# Generated by FakeRAM 2.0 (routing-friendly)
VERSION 5.7 ;
BUSBITCHARS "[]" ;
PROPERTYDEFINITIONS
  MACRO width INTEGER ;
  MACRO depth INTEGER ;
  MACRO banks INTEGER ;
END PROPERTYDEFINITIONS
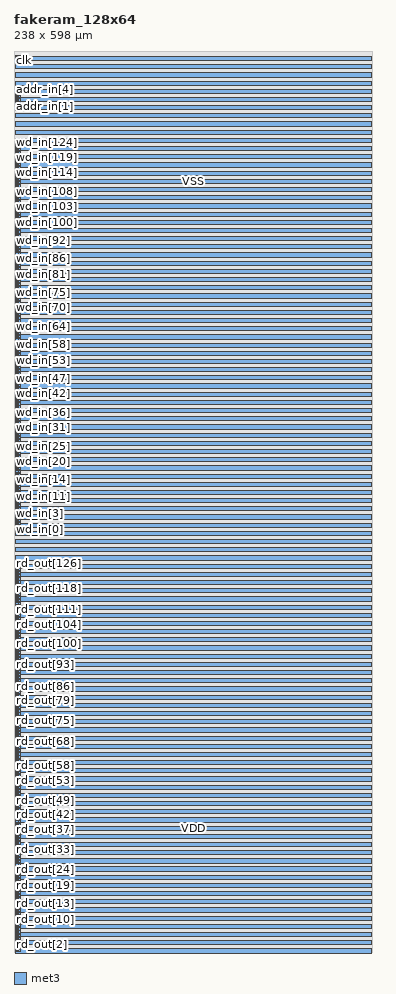
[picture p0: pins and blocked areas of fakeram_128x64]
MACRO fakeram_128x64
  PROPERTY width 128 ;
  PROPERTY depth 64 ;
  PROPERTY banks 1 ;
  FOREIGN fakeram_128x64 0 0 ;
  SYMMETRY X Y R90 ;
  SIZE 238.000 BY 598.000 ;
  CLASS BLOCK ;
  PIN rd_out[0]
    DIRECTION OUTPUT ;
    USE SIGNAL ;
    PORT
      LAYER met3 ;
      RECT 1.000 0.680 3.000 1.380 ;
    END
    PORT
      LAYER met3 ;
      RECT 1.000 0.330 4.000 1.730 ;
    END
  END rd_out[0]
  PIN rd_out[1]
    DIRECTION OUTPUT ;
    USE SIGNAL ;
    PORT
      LAYER met3 ;
      RECT 1.000 2.720 3.000 3.420 ;
    END
    PORT
      LAYER met3 ;
      RECT 1.000 2.370 4.000 3.770 ;
    END
  END rd_out[1]
  PIN rd_out[2]
    DIRECTION OUTPUT ;
    USE SIGNAL ;
    PORT
      LAYER met3 ;
      RECT 1.000 4.760 3.000 5.460 ;
    END
    PORT
      LAYER met3 ;
      RECT 1.000 4.410 4.000 5.810 ;
    END
  END rd_out[2]
  PIN rd_out[3]
    DIRECTION OUTPUT ;
    USE SIGNAL ;
    PORT
      LAYER met3 ;
      RECT 1.000 6.800 3.000 7.500 ;
    END
    PORT
      LAYER met3 ;
      RECT 1.000 6.450 4.000 7.850 ;
    END
  END rd_out[3]
  PIN rd_out[4]
    DIRECTION OUTPUT ;
    USE SIGNAL ;
    PORT
      LAYER met3 ;
      RECT 1.000 8.840 3.000 9.540 ;
    END
    PORT
      LAYER met3 ;
      RECT 1.000 8.490 4.000 9.890 ;
    END
  END rd_out[4]
  PIN rd_out[5]
    DIRECTION OUTPUT ;
    USE SIGNAL ;
    PORT
      LAYER met3 ;
      RECT 1.000 10.880 3.000 11.580 ;
    END
    PORT
      LAYER met3 ;
      RECT 1.000 10.530 4.000 11.930 ;
    END
  END rd_out[5]
  PIN rd_out[6]
    DIRECTION OUTPUT ;
    USE SIGNAL ;
    PORT
      LAYER met3 ;
      RECT 1.000 12.920 3.000 13.620 ;
    END
    PORT
      LAYER met3 ;
      RECT 1.000 12.570 4.000 13.970 ;
    END
  END rd_out[6]
  PIN rd_out[7]
    DIRECTION OUTPUT ;
    USE SIGNAL ;
    PORT
      LAYER met3 ;
      RECT 1.000 14.960 3.000 15.660 ;
    END
    PORT
      LAYER met3 ;
      RECT 1.000 14.610 4.000 16.010 ;
    END
  END rd_out[7]
  PIN rd_out[8]
    DIRECTION OUTPUT ;
    USE SIGNAL ;
    PORT
      LAYER met3 ;
      RECT 1.000 17.000 3.000 17.700 ;
    END
    PORT
      LAYER met3 ;
      RECT 1.000 16.650 4.000 18.050 ;
    END
  END rd_out[8]
  PIN rd_out[9]
    DIRECTION OUTPUT ;
    USE SIGNAL ;
    PORT
      LAYER met3 ;
      RECT 1.000 19.040 3.000 19.740 ;
    END
    PORT
      LAYER met3 ;
      RECT 1.000 18.690 4.000 20.090 ;
    END
  END rd_out[9]
  PIN rd_out[10]
    DIRECTION OUTPUT ;
    USE SIGNAL ;
    PORT
      LAYER met3 ;
      RECT 1.000 21.080 3.000 21.780 ;
    END
    PORT
      LAYER met3 ;
      RECT 1.000 20.730 4.000 22.130 ;
    END
  END rd_out[10]
  PIN rd_out[11]
    DIRECTION OUTPUT ;
    USE SIGNAL ;
    PORT
      LAYER met3 ;
      RECT 1.000 23.120 3.000 23.820 ;
    END
    PORT
      LAYER met3 ;
      RECT 1.000 22.770 4.000 24.170 ;
    END
  END rd_out[11]
  PIN rd_out[12]
    DIRECTION OUTPUT ;
    USE SIGNAL ;
    PORT
      LAYER met3 ;
      RECT 1.000 25.160 3.000 25.860 ;
    END
    PORT
      LAYER met3 ;
      RECT 1.000 24.810 4.000 26.210 ;
    END
  END rd_out[12]
  PIN rd_out[13]
    DIRECTION OUTPUT ;
    USE SIGNAL ;
    PORT
      LAYER met3 ;
      RECT 1.000 27.200 3.000 27.900 ;
    END
    PORT
      LAYER met3 ;
      RECT 1.000 26.850 4.000 28.250 ;
    END
  END rd_out[13]
  PIN rd_out[14]
    DIRECTION OUTPUT ;
    USE SIGNAL ;
    PORT
      LAYER met3 ;
      RECT 1.000 29.240 3.000 29.940 ;
    END
    PORT
      LAYER met3 ;
      RECT 1.000 28.890 4.000 30.290 ;
    END
  END rd_out[14]
  PIN rd_out[15]
    DIRECTION OUTPUT ;
    USE SIGNAL ;
    PORT
      LAYER met3 ;
      RECT 1.000 31.280 3.000 31.980 ;
    END
    PORT
      LAYER met3 ;
      RECT 1.000 30.930 4.000 32.330 ;
    END
  END rd_out[15]
  PIN rd_out[16]
    DIRECTION OUTPUT ;
    USE SIGNAL ;
    PORT
      LAYER met3 ;
      RECT 1.000 33.320 3.000 34.020 ;
    END
    PORT
      LAYER met3 ;
      RECT 1.000 32.970 4.000 34.370 ;
    END
  END rd_out[16]
  PIN rd_out[17]
    DIRECTION OUTPUT ;
    USE SIGNAL ;
    PORT
      LAYER met3 ;
      RECT 1.000 35.360 3.000 36.060 ;
    END
    PORT
      LAYER met3 ;
      RECT 1.000 35.010 4.000 36.410 ;
    END
  END rd_out[17]
  PIN rd_out[18]
    DIRECTION OUTPUT ;
    USE SIGNAL ;
    PORT
      LAYER met3 ;
      RECT 1.000 37.400 3.000 38.100 ;
    END
    PORT
      LAYER met3 ;
      RECT 1.000 37.050 4.000 38.450 ;
    END
  END rd_out[18]
  PIN rd_out[19]
    DIRECTION OUTPUT ;
    USE SIGNAL ;
    PORT
      LAYER met3 ;
      RECT 1.000 39.440 3.000 40.140 ;
    END
    PORT
      LAYER met3 ;
      RECT 1.000 39.090 4.000 40.490 ;
    END
  END rd_out[19]
  PIN rd_out[20]
    DIRECTION OUTPUT ;
    USE SIGNAL ;
    PORT
      LAYER met3 ;
      RECT 1.000 41.480 3.000 42.180 ;
    END
    PORT
      LAYER met3 ;
      RECT 1.000 41.130 4.000 42.530 ;
    END
  END rd_out[20]
  PIN rd_out[21]
    DIRECTION OUTPUT ;
    USE SIGNAL ;
    PORT
      LAYER met3 ;
      RECT 1.000 43.520 3.000 44.220 ;
    END
    PORT
      LAYER met3 ;
      RECT 1.000 43.170 4.000 44.570 ;
    END
  END rd_out[21]
  PIN rd_out[22]
    DIRECTION OUTPUT ;
    USE SIGNAL ;
    PORT
      LAYER met3 ;
      RECT 1.000 45.560 3.000 46.260 ;
    END
    PORT
      LAYER met3 ;
      RECT 1.000 45.210 4.000 46.610 ;
    END
  END rd_out[22]
  PIN rd_out[23]
    DIRECTION OUTPUT ;
    USE SIGNAL ;
    PORT
      LAYER met3 ;
      RECT 1.000 47.600 3.000 48.300 ;
    END
    PORT
      LAYER met3 ;
      RECT 1.000 47.250 4.000 48.650 ;
    END
  END rd_out[23]
  PIN rd_out[24]
    DIRECTION OUTPUT ;
    USE SIGNAL ;
    PORT
      LAYER met3 ;
      RECT 1.000 49.640 3.000 50.340 ;
    END
    PORT
      LAYER met3 ;
      RECT 1.000 49.290 4.000 50.690 ;
    END
  END rd_out[24]
  PIN rd_out[25]
    DIRECTION OUTPUT ;
    USE SIGNAL ;
    PORT
      LAYER met3 ;
      RECT 1.000 51.680 3.000 52.380 ;
    END
    PORT
      LAYER met3 ;
      RECT 1.000 51.330 4.000 52.730 ;
    END
  END rd_out[25]
  PIN rd_out[26]
    DIRECTION OUTPUT ;
    USE SIGNAL ;
    PORT
      LAYER met3 ;
      RECT 1.000 53.720 3.000 54.420 ;
    END
    PORT
      LAYER met3 ;
      RECT 1.000 53.370 4.000 54.770 ;
    END
  END rd_out[26]
  PIN rd_out[27]
    DIRECTION OUTPUT ;
    USE SIGNAL ;
    PORT
      LAYER met3 ;
      RECT 1.000 55.760 3.000 56.460 ;
    END
    PORT
      LAYER met3 ;
      RECT 1.000 55.410 4.000 56.810 ;
    END
  END rd_out[27]
  PIN rd_out[28]
    DIRECTION OUTPUT ;
    USE SIGNAL ;
    PORT
      LAYER met3 ;
      RECT 1.000 57.800 3.000 58.500 ;
    END
    PORT
      LAYER met3 ;
      RECT 1.000 57.450 4.000 58.850 ;
    END
  END rd_out[28]
  PIN rd_out[29]
    DIRECTION OUTPUT ;
    USE SIGNAL ;
    PORT
      LAYER met3 ;
      RECT 1.000 59.840 3.000 60.540 ;
    END
    PORT
      LAYER met3 ;
      RECT 1.000 59.490 4.000 60.890 ;
    END
  END rd_out[29]
  PIN rd_out[30]
    DIRECTION OUTPUT ;
    USE SIGNAL ;
    PORT
      LAYER met3 ;
      RECT 1.000 61.880 3.000 62.580 ;
    END
    PORT
      LAYER met3 ;
      RECT 1.000 61.530 4.000 62.930 ;
    END
  END rd_out[30]
  PIN rd_out[31]
    DIRECTION OUTPUT ;
    USE SIGNAL ;
    PORT
      LAYER met3 ;
      RECT 1.000 63.920 3.000 64.620 ;
    END
    PORT
      LAYER met3 ;
      RECT 1.000 63.570 4.000 64.970 ;
    END
  END rd_out[31]
  PIN rd_out[32]
    DIRECTION OUTPUT ;
    USE SIGNAL ;
    PORT
      LAYER met3 ;
      RECT 1.000 65.960 3.000 66.660 ;
    END
    PORT
      LAYER met3 ;
      RECT 1.000 65.610 4.000 67.010 ;
    END
  END rd_out[32]
  PIN rd_out[33]
    DIRECTION OUTPUT ;
    USE SIGNAL ;
    PORT
      LAYER met3 ;
      RECT 1.000 68.000 3.000 68.700 ;
    END
    PORT
      LAYER met3 ;
      RECT 1.000 67.650 4.000 69.050 ;
    END
  END rd_out[33]
  PIN rd_out[34]
    DIRECTION OUTPUT ;
    USE SIGNAL ;
    PORT
      LAYER met3 ;
      RECT 1.000 70.040 3.000 70.740 ;
    END
    PORT
      LAYER met3 ;
      RECT 1.000 69.690 4.000 71.090 ;
    END
  END rd_out[34]
  PIN rd_out[35]
    DIRECTION OUTPUT ;
    USE SIGNAL ;
    PORT
      LAYER met3 ;
      RECT 1.000 72.080 3.000 72.780 ;
    END
    PORT
      LAYER met3 ;
      RECT 1.000 71.730 4.000 73.130 ;
    END
  END rd_out[35]
  PIN rd_out[36]
    DIRECTION OUTPUT ;
    USE SIGNAL ;
    PORT
      LAYER met3 ;
      RECT 1.000 74.120 3.000 74.820 ;
    END
    PORT
      LAYER met3 ;
      RECT 1.000 73.770 4.000 75.170 ;
    END
  END rd_out[36]
  PIN rd_out[37]
    DIRECTION OUTPUT ;
    USE SIGNAL ;
    PORT
      LAYER met3 ;
      RECT 1.000 76.160 3.000 76.860 ;
    END
    PORT
      LAYER met3 ;
      RECT 1.000 75.810 4.000 77.210 ;
    END
  END rd_out[37]
  PIN rd_out[38]
    DIRECTION OUTPUT ;
    USE SIGNAL ;
    PORT
      LAYER met3 ;
      RECT 1.000 78.200 3.000 78.900 ;
    END
    PORT
      LAYER met3 ;
      RECT 1.000 77.850 4.000 79.250 ;
    END
  END rd_out[38]
  PIN rd_out[39]
    DIRECTION OUTPUT ;
    USE SIGNAL ;
    PORT
      LAYER met3 ;
      RECT 1.000 80.240 3.000 80.940 ;
    END
    PORT
      LAYER met3 ;
      RECT 1.000 79.890 4.000 81.290 ;
    END
  END rd_out[39]
  PIN rd_out[40]
    DIRECTION OUTPUT ;
    USE SIGNAL ;
    PORT
      LAYER met3 ;
      RECT 1.000 82.280 3.000 82.980 ;
    END
    PORT
      LAYER met3 ;
      RECT 1.000 81.930 4.000 83.330 ;
    END
  END rd_out[40]
  PIN rd_out[41]
    DIRECTION OUTPUT ;
    USE SIGNAL ;
    PORT
      LAYER met3 ;
      RECT 1.000 84.320 3.000 85.020 ;
    END
    PORT
      LAYER met3 ;
      RECT 1.000 83.970 4.000 85.370 ;
    END
  END rd_out[41]
  PIN rd_out[42]
    DIRECTION OUTPUT ;
    USE SIGNAL ;
    PORT
      LAYER met3 ;
      RECT 1.000 86.360 3.000 87.060 ;
    END
    PORT
      LAYER met3 ;
      RECT 1.000 86.010 4.000 87.410 ;
    END
  END rd_out[42]
  PIN rd_out[43]
    DIRECTION OUTPUT ;
    USE SIGNAL ;
    PORT
      LAYER met3 ;
      RECT 1.000 88.400 3.000 89.100 ;
    END
    PORT
      LAYER met3 ;
      RECT 1.000 88.050 4.000 89.450 ;
    END
  END rd_out[43]
  PIN rd_out[44]
    DIRECTION OUTPUT ;
    USE SIGNAL ;
    PORT
      LAYER met3 ;
      RECT 1.000 90.440 3.000 91.140 ;
    END
    PORT
      LAYER met3 ;
      RECT 1.000 90.090 4.000 91.490 ;
    END
  END rd_out[44]
  PIN rd_out[45]
    DIRECTION OUTPUT ;
    USE SIGNAL ;
    PORT
      LAYER met3 ;
      RECT 1.000 92.480 3.000 93.180 ;
    END
    PORT
      LAYER met3 ;
      RECT 1.000 92.130 4.000 93.530 ;
    END
  END rd_out[45]
  PIN rd_out[46]
    DIRECTION OUTPUT ;
    USE SIGNAL ;
    PORT
      LAYER met3 ;
      RECT 1.000 94.520 3.000 95.220 ;
    END
    PORT
      LAYER met3 ;
      RECT 1.000 94.170 4.000 95.570 ;
    END
  END rd_out[46]
  PIN rd_out[47]
    DIRECTION OUTPUT ;
    USE SIGNAL ;
    PORT
      LAYER met3 ;
      RECT 1.000 96.560 3.000 97.260 ;
    END
    PORT
      LAYER met3 ;
      RECT 1.000 96.210 4.000 97.610 ;
    END
  END rd_out[47]
  PIN rd_out[48]
    DIRECTION OUTPUT ;
    USE SIGNAL ;
    PORT
      LAYER met3 ;
      RECT 1.000 98.600 3.000 99.300 ;
    END
    PORT
      LAYER met3 ;
      RECT 1.000 98.250 4.000 99.650 ;
    END
  END rd_out[48]
  PIN rd_out[49]
    DIRECTION OUTPUT ;
    USE SIGNAL ;
    PORT
      LAYER met3 ;
      RECT 1.000 100.640 3.000 101.340 ;
    END
    PORT
      LAYER met3 ;
      RECT 1.000 100.290 4.000 101.690 ;
    END
  END rd_out[49]
  PIN rd_out[50]
    DIRECTION OUTPUT ;
    USE SIGNAL ;
    PORT
      LAYER met3 ;
      RECT 1.000 102.680 3.000 103.380 ;
    END
    PORT
      LAYER met3 ;
      RECT 1.000 102.330 4.000 103.730 ;
    END
  END rd_out[50]
  PIN rd_out[51]
    DIRECTION OUTPUT ;
    USE SIGNAL ;
    PORT
      LAYER met3 ;
      RECT 1.000 104.720 3.000 105.420 ;
    END
    PORT
      LAYER met3 ;
      RECT 1.000 104.370 4.000 105.770 ;
    END
  END rd_out[51]
  PIN rd_out[52]
    DIRECTION OUTPUT ;
    USE SIGNAL ;
    PORT
      LAYER met3 ;
      RECT 1.000 106.760 3.000 107.460 ;
    END
    PORT
      LAYER met3 ;
      RECT 1.000 106.410 4.000 107.810 ;
    END
  END rd_out[52]
  PIN rd_out[53]
    DIRECTION OUTPUT ;
    USE SIGNAL ;
    PORT
      LAYER met3 ;
      RECT 1.000 108.800 3.000 109.500 ;
    END
    PORT
      LAYER met3 ;
      RECT 1.000 108.450 4.000 109.850 ;
    END
  END rd_out[53]
  PIN rd_out[54]
    DIRECTION OUTPUT ;
    USE SIGNAL ;
    PORT
      LAYER met3 ;
      RECT 1.000 110.840 3.000 111.540 ;
    END
    PORT
      LAYER met3 ;
      RECT 1.000 110.490 4.000 111.890 ;
    END
  END rd_out[54]
  PIN rd_out[55]
    DIRECTION OUTPUT ;
    USE SIGNAL ;
    PORT
      LAYER met3 ;
      RECT 1.000 112.880 3.000 113.580 ;
    END
    PORT
      LAYER met3 ;
      RECT 1.000 112.530 4.000 113.930 ;
    END
  END rd_out[55]
  PIN rd_out[56]
    DIRECTION OUTPUT ;
    USE SIGNAL ;
    PORT
      LAYER met3 ;
      RECT 1.000 114.920 3.000 115.620 ;
    END
    PORT
      LAYER met3 ;
      RECT 1.000 114.570 4.000 115.970 ;
    END
  END rd_out[56]
  PIN rd_out[57]
    DIRECTION OUTPUT ;
    USE SIGNAL ;
    PORT
      LAYER met3 ;
      RECT 1.000 116.960 3.000 117.660 ;
    END
    PORT
      LAYER met3 ;
      RECT 1.000 116.610 4.000 118.010 ;
    END
  END rd_out[57]
  PIN rd_out[58]
    DIRECTION OUTPUT ;
    USE SIGNAL ;
    PORT
      LAYER met3 ;
      RECT 1.000 119.000 3.000 119.700 ;
    END
    PORT
      LAYER met3 ;
      RECT 1.000 118.650 4.000 120.050 ;
    END
  END rd_out[58]
  PIN rd_out[59]
    DIRECTION OUTPUT ;
    USE SIGNAL ;
    PORT
      LAYER met3 ;
      RECT 1.000 121.040 3.000 121.740 ;
    END
    PORT
      LAYER met3 ;
      RECT 1.000 120.690 4.000 122.090 ;
    END
  END rd_out[59]
  PIN rd_out[60]
    DIRECTION OUTPUT ;
    USE SIGNAL ;
    PORT
      LAYER met3 ;
      RECT 1.000 123.080 3.000 123.780 ;
    END
    PORT
      LAYER met3 ;
      RECT 1.000 122.730 4.000 124.130 ;
    END
  END rd_out[60]
  PIN rd_out[61]
    DIRECTION OUTPUT ;
    USE SIGNAL ;
    PORT
      LAYER met3 ;
      RECT 1.000 125.120 3.000 125.820 ;
    END
    PORT
      LAYER met3 ;
      RECT 1.000 124.770 4.000 126.170 ;
    END
  END rd_out[61]
  PIN rd_out[62]
    DIRECTION OUTPUT ;
    USE SIGNAL ;
    PORT
      LAYER met3 ;
      RECT 1.000 127.160 3.000 127.860 ;
    END
    PORT
      LAYER met3 ;
      RECT 1.000 126.810 4.000 128.210 ;
    END
  END rd_out[62]
  PIN rd_out[63]
    DIRECTION OUTPUT ;
    USE SIGNAL ;
    PORT
      LAYER met3 ;
      RECT 1.000 129.200 3.000 129.900 ;
    END
    PORT
      LAYER met3 ;
      RECT 1.000 128.850 4.000 130.250 ;
    END
  END rd_out[63]
  PIN rd_out[64]
    DIRECTION OUTPUT ;
    USE SIGNAL ;
    PORT
      LAYER met3 ;
      RECT 1.000 131.240 3.000 131.940 ;
    END
    PORT
      LAYER met3 ;
      RECT 1.000 130.890 4.000 132.290 ;
    END
  END rd_out[64]
  PIN rd_out[65]
    DIRECTION OUTPUT ;
    USE SIGNAL ;
    PORT
      LAYER met3 ;
      RECT 1.000 133.280 3.000 133.980 ;
    END
    PORT
      LAYER met3 ;
      RECT 1.000 132.930 4.000 134.330 ;
    END
  END rd_out[65]
  PIN rd_out[66]
    DIRECTION OUTPUT ;
    USE SIGNAL ;
    PORT
      LAYER met3 ;
      RECT 1.000 135.320 3.000 136.020 ;
    END
    PORT
      LAYER met3 ;
      RECT 1.000 134.970 4.000 136.370 ;
    END
  END rd_out[66]
  PIN rd_out[67]
    DIRECTION OUTPUT ;
    USE SIGNAL ;
    PORT
      LAYER met3 ;
      RECT 1.000 137.360 3.000 138.060 ;
    END
    PORT
      LAYER met3 ;
      RECT 1.000 137.010 4.000 138.410 ;
    END
  END rd_out[67]
  PIN rd_out[68]
    DIRECTION OUTPUT ;
    USE SIGNAL ;
    PORT
      LAYER met3 ;
      RECT 1.000 139.400 3.000 140.100 ;
    END
    PORT
      LAYER met3 ;
      RECT 1.000 139.050 4.000 140.450 ;
    END
  END rd_out[68]
  PIN rd_out[69]
    DIRECTION OUTPUT ;
    USE SIGNAL ;
    PORT
      LAYER met3 ;
      RECT 1.000 141.440 3.000 142.140 ;
    END
    PORT
      LAYER met3 ;
      RECT 1.000 141.090 4.000 142.490 ;
    END
  END rd_out[69]
  PIN rd_out[70]
    DIRECTION OUTPUT ;
    USE SIGNAL ;
    PORT
      LAYER met3 ;
      RECT 1.000 143.480 3.000 144.180 ;
    END
    PORT
      LAYER met3 ;
      RECT 1.000 143.130 4.000 144.530 ;
    END
  END rd_out[70]
  PIN rd_out[71]
    DIRECTION OUTPUT ;
    USE SIGNAL ;
    PORT
      LAYER met3 ;
      RECT 1.000 145.520 3.000 146.220 ;
    END
    PORT
      LAYER met3 ;
      RECT 1.000 145.170 4.000 146.570 ;
    END
  END rd_out[71]
  PIN rd_out[72]
    DIRECTION OUTPUT ;
    USE SIGNAL ;
    PORT
      LAYER met3 ;
      RECT 1.000 147.560 3.000 148.260 ;
    END
    PORT
      LAYER met3 ;
      RECT 1.000 147.210 4.000 148.610 ;
    END
  END rd_out[72]
  PIN rd_out[73]
    DIRECTION OUTPUT ;
    USE SIGNAL ;
    PORT
      LAYER met3 ;
      RECT 1.000 149.600 3.000 150.300 ;
    END
    PORT
      LAYER met3 ;
      RECT 1.000 149.250 4.000 150.650 ;
    END
  END rd_out[73]
  PIN rd_out[74]
    DIRECTION OUTPUT ;
    USE SIGNAL ;
    PORT
      LAYER met3 ;
      RECT 1.000 151.640 3.000 152.340 ;
    END
    PORT
      LAYER met3 ;
      RECT 1.000 151.290 4.000 152.690 ;
    END
  END rd_out[74]
  PIN rd_out[75]
    DIRECTION OUTPUT ;
    USE SIGNAL ;
    PORT
      LAYER met3 ;
      RECT 1.000 153.680 3.000 154.380 ;
    END
    PORT
      LAYER met3 ;
      RECT 1.000 153.330 4.000 154.730 ;
    END
  END rd_out[75]
  PIN rd_out[76]
    DIRECTION OUTPUT ;
    USE SIGNAL ;
    PORT
      LAYER met3 ;
      RECT 1.000 155.720 3.000 156.420 ;
    END
    PORT
      LAYER met3 ;
      RECT 1.000 155.370 4.000 156.770 ;
    END
  END rd_out[76]
  PIN rd_out[77]
    DIRECTION OUTPUT ;
    USE SIGNAL ;
    PORT
      LAYER met3 ;
      RECT 1.000 157.760 3.000 158.460 ;
    END
    PORT
      LAYER met3 ;
      RECT 1.000 157.410 4.000 158.810 ;
    END
  END rd_out[77]
  PIN rd_out[78]
    DIRECTION OUTPUT ;
    USE SIGNAL ;
    PORT
      LAYER met3 ;
      RECT 1.000 159.800 3.000 160.500 ;
    END
    PORT
      LAYER met3 ;
      RECT 1.000 159.450 4.000 160.850 ;
    END
  END rd_out[78]
  PIN rd_out[79]
    DIRECTION OUTPUT ;
    USE SIGNAL ;
    PORT
      LAYER met3 ;
      RECT 1.000 161.840 3.000 162.540 ;
    END
    PORT
      LAYER met3 ;
      RECT 1.000 161.490 4.000 162.890 ;
    END
  END rd_out[79]
  PIN rd_out[80]
    DIRECTION OUTPUT ;
    USE SIGNAL ;
    PORT
      LAYER met3 ;
      RECT 1.000 163.880 3.000 164.580 ;
    END
    PORT
      LAYER met3 ;
      RECT 1.000 163.530 4.000 164.930 ;
    END
  END rd_out[80]
  PIN rd_out[81]
    DIRECTION OUTPUT ;
    USE SIGNAL ;
    PORT
      LAYER met3 ;
      RECT 1.000 165.920 3.000 166.620 ;
    END
    PORT
      LAYER met3 ;
      RECT 1.000 165.570 4.000 166.970 ;
    END
  END rd_out[81]
  PIN rd_out[82]
    DIRECTION OUTPUT ;
    USE SIGNAL ;
    PORT
      LAYER met3 ;
      RECT 1.000 167.960 3.000 168.660 ;
    END
    PORT
      LAYER met3 ;
      RECT 1.000 167.610 4.000 169.010 ;
    END
  END rd_out[82]
  PIN rd_out[83]
    DIRECTION OUTPUT ;
    USE SIGNAL ;
    PORT
      LAYER met3 ;
      RECT 1.000 170.000 3.000 170.700 ;
    END
    PORT
      LAYER met3 ;
      RECT 1.000 169.650 4.000 171.050 ;
    END
  END rd_out[83]
  PIN rd_out[84]
    DIRECTION OUTPUT ;
    USE SIGNAL ;
    PORT
      LAYER met3 ;
      RECT 1.000 172.040 3.000 172.740 ;
    END
    PORT
      LAYER met3 ;
      RECT 1.000 171.690 4.000 173.090 ;
    END
  END rd_out[84]
  PIN rd_out[85]
    DIRECTION OUTPUT ;
    USE SIGNAL ;
    PORT
      LAYER met3 ;
      RECT 1.000 174.080 3.000 174.780 ;
    END
    PORT
      LAYER met3 ;
      RECT 1.000 173.730 4.000 175.130 ;
    END
  END rd_out[85]
  PIN rd_out[86]
    DIRECTION OUTPUT ;
    USE SIGNAL ;
    PORT
      LAYER met3 ;
      RECT 1.000 176.120 3.000 176.820 ;
    END
    PORT
      LAYER met3 ;
      RECT 1.000 175.770 4.000 177.170 ;
    END
  END rd_out[86]
  PIN rd_out[87]
    DIRECTION OUTPUT ;
    USE SIGNAL ;
    PORT
      LAYER met3 ;
      RECT 1.000 178.160 3.000 178.860 ;
    END
    PORT
      LAYER met3 ;
      RECT 1.000 177.810 4.000 179.210 ;
    END
  END rd_out[87]
  PIN rd_out[88]
    DIRECTION OUTPUT ;
    USE SIGNAL ;
    PORT
      LAYER met3 ;
      RECT 1.000 180.200 3.000 180.900 ;
    END
    PORT
      LAYER met3 ;
      RECT 1.000 179.850 4.000 181.250 ;
    END
  END rd_out[88]
  PIN rd_out[89]
    DIRECTION OUTPUT ;
    USE SIGNAL ;
    PORT
      LAYER met3 ;
      RECT 1.000 182.240 3.000 182.940 ;
    END
    PORT
      LAYER met3 ;
      RECT 1.000 181.890 4.000 183.290 ;
    END
  END rd_out[89]
  PIN rd_out[90]
    DIRECTION OUTPUT ;
    USE SIGNAL ;
    PORT
      LAYER met3 ;
      RECT 1.000 184.280 3.000 184.980 ;
    END
    PORT
      LAYER met3 ;
      RECT 1.000 183.930 4.000 185.330 ;
    END
  END rd_out[90]
  PIN rd_out[91]
    DIRECTION OUTPUT ;
    USE SIGNAL ;
    PORT
      LAYER met3 ;
      RECT 1.000 186.320 3.000 187.020 ;
    END
    PORT
      LAYER met3 ;
      RECT 1.000 185.970 4.000 187.370 ;
    END
  END rd_out[91]
  PIN rd_out[92]
    DIRECTION OUTPUT ;
    USE SIGNAL ;
    PORT
      LAYER met3 ;
      RECT 1.000 188.360 3.000 189.060 ;
    END
    PORT
      LAYER met3 ;
      RECT 1.000 188.010 4.000 189.410 ;
    END
  END rd_out[92]
  PIN rd_out[93]
    DIRECTION OUTPUT ;
    USE SIGNAL ;
    PORT
      LAYER met3 ;
      RECT 1.000 190.400 3.000 191.100 ;
    END
    PORT
      LAYER met3 ;
      RECT 1.000 190.050 4.000 191.450 ;
    END
  END rd_out[93]
  PIN rd_out[94]
    DIRECTION OUTPUT ;
    USE SIGNAL ;
    PORT
      LAYER met3 ;
      RECT 1.000 192.440 3.000 193.140 ;
    END
    PORT
      LAYER met3 ;
      RECT 1.000 192.090 4.000 193.490 ;
    END
  END rd_out[94]
  PIN rd_out[95]
    DIRECTION OUTPUT ;
    USE SIGNAL ;
    PORT
      LAYER met3 ;
      RECT 1.000 194.480 3.000 195.180 ;
    END
    PORT
      LAYER met3 ;
      RECT 1.000 194.130 4.000 195.530 ;
    END
  END rd_out[95]
  PIN rd_out[96]
    DIRECTION OUTPUT ;
    USE SIGNAL ;
    PORT
      LAYER met3 ;
      RECT 1.000 196.520 3.000 197.220 ;
    END
    PORT
      LAYER met3 ;
      RECT 1.000 196.170 4.000 197.570 ;
    END
  END rd_out[96]
  PIN rd_out[97]
    DIRECTION OUTPUT ;
    USE SIGNAL ;
    PORT
      LAYER met3 ;
      RECT 1.000 198.560 3.000 199.260 ;
    END
    PORT
      LAYER met3 ;
      RECT 1.000 198.210 4.000 199.610 ;
    END
  END rd_out[97]
  PIN rd_out[98]
    DIRECTION OUTPUT ;
    USE SIGNAL ;
    PORT
      LAYER met3 ;
      RECT 1.000 200.600 3.000 201.300 ;
    END
    PORT
      LAYER met3 ;
      RECT 1.000 200.250 4.000 201.650 ;
    END
  END rd_out[98]
  PIN rd_out[99]
    DIRECTION OUTPUT ;
    USE SIGNAL ;
    PORT
      LAYER met3 ;
      RECT 1.000 202.640 3.000 203.340 ;
    END
    PORT
      LAYER met3 ;
      RECT 1.000 202.290 4.000 203.690 ;
    END
  END rd_out[99]
  PIN rd_out[100]
    DIRECTION OUTPUT ;
    USE SIGNAL ;
    PORT
      LAYER met3 ;
      RECT 1.000 204.680 3.000 205.380 ;
    END
    PORT
      LAYER met3 ;
      RECT 1.000 204.330 4.000 205.730 ;
    END
  END rd_out[100]
  PIN rd_out[101]
    DIRECTION OUTPUT ;
    USE SIGNAL ;
    PORT
      LAYER met3 ;
      RECT 1.000 206.720 3.000 207.420 ;
    END
    PORT
      LAYER met3 ;
      RECT 1.000 206.370 4.000 207.770 ;
    END
  END rd_out[101]
  PIN rd_out[102]
    DIRECTION OUTPUT ;
    USE SIGNAL ;
    PORT
      LAYER met3 ;
      RECT 1.000 208.760 3.000 209.460 ;
    END
    PORT
      LAYER met3 ;
      RECT 1.000 208.410 4.000 209.810 ;
    END
  END rd_out[102]
  PIN rd_out[103]
    DIRECTION OUTPUT ;
    USE SIGNAL ;
    PORT
      LAYER met3 ;
      RECT 1.000 210.800 3.000 211.500 ;
    END
    PORT
      LAYER met3 ;
      RECT 1.000 210.450 4.000 211.850 ;
    END
  END rd_out[103]
  PIN rd_out[104]
    DIRECTION OUTPUT ;
    USE SIGNAL ;
    PORT
      LAYER met3 ;
      RECT 1.000 212.840 3.000 213.540 ;
    END
    PORT
      LAYER met3 ;
      RECT 1.000 212.490 4.000 213.890 ;
    END
  END rd_out[104]
  PIN rd_out[105]
    DIRECTION OUTPUT ;
    USE SIGNAL ;
    PORT
      LAYER met3 ;
      RECT 1.000 214.880 3.000 215.580 ;
    END
    PORT
      LAYER met3 ;
      RECT 1.000 214.530 4.000 215.930 ;
    END
  END rd_out[105]
  PIN rd_out[106]
    DIRECTION OUTPUT ;
    USE SIGNAL ;
    PORT
      LAYER met3 ;
      RECT 1.000 216.920 3.000 217.620 ;
    END
    PORT
      LAYER met3 ;
      RECT 1.000 216.570 4.000 217.970 ;
    END
  END rd_out[106]
  PIN rd_out[107]
    DIRECTION OUTPUT ;
    USE SIGNAL ;
    PORT
      LAYER met3 ;
      RECT 1.000 218.960 3.000 219.660 ;
    END
    PORT
      LAYER met3 ;
      RECT 1.000 218.610 4.000 220.010 ;
    END
  END rd_out[107]
  PIN rd_out[108]
    DIRECTION OUTPUT ;
    USE SIGNAL ;
    PORT
      LAYER met3 ;
      RECT 1.000 221.000 3.000 221.700 ;
    END
    PORT
      LAYER met3 ;
      RECT 1.000 220.650 4.000 222.050 ;
    END
  END rd_out[108]
  PIN rd_out[109]
    DIRECTION OUTPUT ;
    USE SIGNAL ;
    PORT
      LAYER met3 ;
      RECT 1.000 223.040 3.000 223.740 ;
    END
    PORT
      LAYER met3 ;
      RECT 1.000 222.690 4.000 224.090 ;
    END
  END rd_out[109]
  PIN rd_out[110]
    DIRECTION OUTPUT ;
    USE SIGNAL ;
    PORT
      LAYER met3 ;
      RECT 1.000 225.080 3.000 225.780 ;
    END
    PORT
      LAYER met3 ;
      RECT 1.000 224.730 4.000 226.130 ;
    END
  END rd_out[110]
  PIN rd_out[111]
    DIRECTION OUTPUT ;
    USE SIGNAL ;
    PORT
      LAYER met3 ;
      RECT 1.000 227.120 3.000 227.820 ;
    END
    PORT
      LAYER met3 ;
      RECT 1.000 226.770 4.000 228.170 ;
    END
  END rd_out[111]
  PIN rd_out[112]
    DIRECTION OUTPUT ;
    USE SIGNAL ;
    PORT
      LAYER met3 ;
      RECT 1.000 229.160 3.000 229.860 ;
    END
    PORT
      LAYER met3 ;
      RECT 1.000 228.810 4.000 230.210 ;
    END
  END rd_out[112]
  PIN rd_out[113]
    DIRECTION OUTPUT ;
    USE SIGNAL ;
    PORT
      LAYER met3 ;
      RECT 1.000 231.200 3.000 231.900 ;
    END
    PORT
      LAYER met3 ;
      RECT 1.000 230.850 4.000 232.250 ;
    END
  END rd_out[113]
  PIN rd_out[114]
    DIRECTION OUTPUT ;
    USE SIGNAL ;
    PORT
      LAYER met3 ;
      RECT 1.000 233.240 3.000 233.940 ;
    END
    PORT
      LAYER met3 ;
      RECT 1.000 232.890 4.000 234.290 ;
    END
  END rd_out[114]
  PIN rd_out[115]
    DIRECTION OUTPUT ;
    USE SIGNAL ;
    PORT
      LAYER met3 ;
      RECT 1.000 235.280 3.000 235.980 ;
    END
    PORT
      LAYER met3 ;
      RECT 1.000 234.930 4.000 236.330 ;
    END
  END rd_out[115]
  PIN rd_out[116]
    DIRECTION OUTPUT ;
    USE SIGNAL ;
    PORT
      LAYER met3 ;
      RECT 1.000 237.320 3.000 238.020 ;
    END
    PORT
      LAYER met3 ;
      RECT 1.000 236.970 4.000 238.370 ;
    END
  END rd_out[116]
  PIN rd_out[117]
    DIRECTION OUTPUT ;
    USE SIGNAL ;
    PORT
      LAYER met3 ;
      RECT 1.000 239.360 3.000 240.060 ;
    END
    PORT
      LAYER met3 ;
      RECT 1.000 239.010 4.000 240.410 ;
    END
  END rd_out[117]
  PIN rd_out[118]
    DIRECTION OUTPUT ;
    USE SIGNAL ;
    PORT
      LAYER met3 ;
      RECT 1.000 241.400 3.000 242.100 ;
    END
    PORT
      LAYER met3 ;
      RECT 1.000 241.050 4.000 242.450 ;
    END
  END rd_out[118]
  PIN rd_out[119]
    DIRECTION OUTPUT ;
    USE SIGNAL ;
    PORT
      LAYER met3 ;
      RECT 1.000 243.440 3.000 244.140 ;
    END
    PORT
      LAYER met3 ;
      RECT 1.000 243.090 4.000 244.490 ;
    END
  END rd_out[119]
  PIN rd_out[120]
    DIRECTION OUTPUT ;
    USE SIGNAL ;
    PORT
      LAYER met3 ;
      RECT 1.000 245.480 3.000 246.180 ;
    END
    PORT
      LAYER met3 ;
      RECT 1.000 245.130 4.000 246.530 ;
    END
  END rd_out[120]
  PIN rd_out[121]
    DIRECTION OUTPUT ;
    USE SIGNAL ;
    PORT
      LAYER met3 ;
      RECT 1.000 247.520 3.000 248.220 ;
    END
    PORT
      LAYER met3 ;
      RECT 1.000 247.170 4.000 248.570 ;
    END
  END rd_out[121]
  PIN rd_out[122]
    DIRECTION OUTPUT ;
    USE SIGNAL ;
    PORT
      LAYER met3 ;
      RECT 1.000 249.560 3.000 250.260 ;
    END
    PORT
      LAYER met3 ;
      RECT 1.000 249.210 4.000 250.610 ;
    END
  END rd_out[122]
  PIN rd_out[123]
    DIRECTION OUTPUT ;
    USE SIGNAL ;
    PORT
      LAYER met3 ;
      RECT 1.000 251.600 3.000 252.300 ;
    END
    PORT
      LAYER met3 ;
      RECT 1.000 251.250 4.000 252.650 ;
    END
  END rd_out[123]
  PIN rd_out[124]
    DIRECTION OUTPUT ;
    USE SIGNAL ;
    PORT
      LAYER met3 ;
      RECT 1.000 253.640 3.000 254.340 ;
    END
    PORT
      LAYER met3 ;
      RECT 1.000 253.290 4.000 254.690 ;
    END
  END rd_out[124]
  PIN rd_out[125]
    DIRECTION OUTPUT ;
    USE SIGNAL ;
    PORT
      LAYER met3 ;
      RECT 1.000 255.680 3.000 256.380 ;
    END
    PORT
      LAYER met3 ;
      RECT 1.000 255.330 4.000 256.730 ;
    END
  END rd_out[125]
  PIN rd_out[126]
    DIRECTION OUTPUT ;
    USE SIGNAL ;
    PORT
      LAYER met3 ;
      RECT 1.000 257.720 3.000 258.420 ;
    END
    PORT
      LAYER met3 ;
      RECT 1.000 257.370 4.000 258.770 ;
    END
  END rd_out[126]
  PIN rd_out[127]
    DIRECTION OUTPUT ;
    USE SIGNAL ;
    PORT
      LAYER met3 ;
      RECT 1.000 259.760 3.000 260.460 ;
    END
    PORT
      LAYER met3 ;
      RECT 1.000 259.410 4.000 260.810 ;
    END
  END rd_out[127]
  PIN wd_in[0]
    DIRECTION INPUT ;
    USE SIGNAL ;
    PORT
      LAYER met3 ;
      RECT 1.000 280.160 3.000 280.860 ;
    END
    PORT
      LAYER met3 ;
      RECT 1.000 279.810 4.000 281.210 ;
    END
  END wd_in[0]
  PIN wd_in[1]
    DIRECTION INPUT ;
    USE SIGNAL ;
    PORT
      LAYER met3 ;
      RECT 1.000 282.200 3.000 282.900 ;
    END
    PORT
      LAYER met3 ;
      RECT 1.000 281.850 4.000 283.250 ;
    END
  END wd_in[1]
  PIN wd_in[2]
    DIRECTION INPUT ;
    USE SIGNAL ;
    PORT
      LAYER met3 ;
      RECT 1.000 284.240 3.000 284.940 ;
    END
    PORT
      LAYER met3 ;
      RECT 1.000 283.890 4.000 285.290 ;
    END
  END wd_in[2]
  PIN wd_in[3]
    DIRECTION INPUT ;
    USE SIGNAL ;
    PORT
      LAYER met3 ;
      RECT 1.000 286.280 3.000 286.980 ;
    END
    PORT
      LAYER met3 ;
      RECT 1.000 285.930 4.000 287.330 ;
    END
  END wd_in[3]
  PIN wd_in[4]
    DIRECTION INPUT ;
    USE SIGNAL ;
    PORT
      LAYER met3 ;
      RECT 1.000 288.320 3.000 289.020 ;
    END
    PORT
      LAYER met3 ;
      RECT 1.000 287.970 4.000 289.370 ;
    END
  END wd_in[4]
  PIN wd_in[5]
    DIRECTION INPUT ;
    USE SIGNAL ;
    PORT
      LAYER met3 ;
      RECT 1.000 290.360 3.000 291.060 ;
    END
    PORT
      LAYER met3 ;
      RECT 1.000 290.010 4.000 291.410 ;
    END
  END wd_in[5]
  PIN wd_in[6]
    DIRECTION INPUT ;
    USE SIGNAL ;
    PORT
      LAYER met3 ;
      RECT 1.000 292.400 3.000 293.100 ;
    END
    PORT
      LAYER met3 ;
      RECT 1.000 292.050 4.000 293.450 ;
    END
  END wd_in[6]
  PIN wd_in[7]
    DIRECTION INPUT ;
    USE SIGNAL ;
    PORT
      LAYER met3 ;
      RECT 1.000 294.440 3.000 295.140 ;
    END
    PORT
      LAYER met3 ;
      RECT 1.000 294.090 4.000 295.490 ;
    END
  END wd_in[7]
  PIN wd_in[8]
    DIRECTION INPUT ;
    USE SIGNAL ;
    PORT
      LAYER met3 ;
      RECT 1.000 296.480 3.000 297.180 ;
    END
    PORT
      LAYER met3 ;
      RECT 1.000 296.130 4.000 297.530 ;
    END
  END wd_in[8]
  PIN wd_in[9]
    DIRECTION INPUT ;
    USE SIGNAL ;
    PORT
      LAYER met3 ;
      RECT 1.000 298.520 3.000 299.220 ;
    END
    PORT
      LAYER met3 ;
      RECT 1.000 298.170 4.000 299.570 ;
    END
  END wd_in[9]
  PIN wd_in[10]
    DIRECTION INPUT ;
    USE SIGNAL ;
    PORT
      LAYER met3 ;
      RECT 1.000 300.560 3.000 301.260 ;
    END
    PORT
      LAYER met3 ;
      RECT 1.000 300.210 4.000 301.610 ;
    END
  END wd_in[10]
  PIN wd_in[11]
    DIRECTION INPUT ;
    USE SIGNAL ;
    PORT
      LAYER met3 ;
      RECT 1.000 302.600 3.000 303.300 ;
    END
    PORT
      LAYER met3 ;
      RECT 1.000 302.250 4.000 303.650 ;
    END
  END wd_in[11]
  PIN wd_in[12]
    DIRECTION INPUT ;
    USE SIGNAL ;
    PORT
      LAYER met3 ;
      RECT 1.000 304.640 3.000 305.340 ;
    END
    PORT
      LAYER met3 ;
      RECT 1.000 304.290 4.000 305.690 ;
    END
  END wd_in[12]
  PIN wd_in[13]
    DIRECTION INPUT ;
    USE SIGNAL ;
    PORT
      LAYER met3 ;
      RECT 1.000 306.680 3.000 307.380 ;
    END
    PORT
      LAYER met3 ;
      RECT 1.000 306.330 4.000 307.730 ;
    END
  END wd_in[13]
  PIN wd_in[14]
    DIRECTION INPUT ;
    USE SIGNAL ;
    PORT
      LAYER met3 ;
      RECT 1.000 308.720 3.000 309.420 ;
    END
    PORT
      LAYER met3 ;
      RECT 1.000 308.370 4.000 309.770 ;
    END
  END wd_in[14]
  PIN wd_in[15]
    DIRECTION INPUT ;
    USE SIGNAL ;
    PORT
      LAYER met3 ;
      RECT 1.000 310.760 3.000 311.460 ;
    END
    PORT
      LAYER met3 ;
      RECT 1.000 310.410 4.000 311.810 ;
    END
  END wd_in[15]
  PIN wd_in[16]
    DIRECTION INPUT ;
    USE SIGNAL ;
    PORT
      LAYER met3 ;
      RECT 1.000 312.800 3.000 313.500 ;
    END
    PORT
      LAYER met3 ;
      RECT 1.000 312.450 4.000 313.850 ;
    END
  END wd_in[16]
  PIN wd_in[17]
    DIRECTION INPUT ;
    USE SIGNAL ;
    PORT
      LAYER met3 ;
      RECT 1.000 314.840 3.000 315.540 ;
    END
    PORT
      LAYER met3 ;
      RECT 1.000 314.490 4.000 315.890 ;
    END
  END wd_in[17]
  PIN wd_in[18]
    DIRECTION INPUT ;
    USE SIGNAL ;
    PORT
      LAYER met3 ;
      RECT 1.000 316.880 3.000 317.580 ;
    END
    PORT
      LAYER met3 ;
      RECT 1.000 316.530 4.000 317.930 ;
    END
  END wd_in[18]
  PIN wd_in[19]
    DIRECTION INPUT ;
    USE SIGNAL ;
    PORT
      LAYER met3 ;
      RECT 1.000 318.920 3.000 319.620 ;
    END
    PORT
      LAYER met3 ;
      RECT 1.000 318.570 4.000 319.970 ;
    END
  END wd_in[19]
  PIN wd_in[20]
    DIRECTION INPUT ;
    USE SIGNAL ;
    PORT
      LAYER met3 ;
      RECT 1.000 320.960 3.000 321.660 ;
    END
    PORT
      LAYER met3 ;
      RECT 1.000 320.610 4.000 322.010 ;
    END
  END wd_in[20]
  PIN wd_in[21]
    DIRECTION INPUT ;
    USE SIGNAL ;
    PORT
      LAYER met3 ;
      RECT 1.000 323.000 3.000 323.700 ;
    END
    PORT
      LAYER met3 ;
      RECT 1.000 322.650 4.000 324.050 ;
    END
  END wd_in[21]
  PIN wd_in[22]
    DIRECTION INPUT ;
    USE SIGNAL ;
    PORT
      LAYER met3 ;
      RECT 1.000 325.040 3.000 325.740 ;
    END
    PORT
      LAYER met3 ;
      RECT 1.000 324.690 4.000 326.090 ;
    END
  END wd_in[22]
  PIN wd_in[23]
    DIRECTION INPUT ;
    USE SIGNAL ;
    PORT
      LAYER met3 ;
      RECT 1.000 327.080 3.000 327.780 ;
    END
    PORT
      LAYER met3 ;
      RECT 1.000 326.730 4.000 328.130 ;
    END
  END wd_in[23]
  PIN wd_in[24]
    DIRECTION INPUT ;
    USE SIGNAL ;
    PORT
      LAYER met3 ;
      RECT 1.000 329.120 3.000 329.820 ;
    END
    PORT
      LAYER met3 ;
      RECT 1.000 328.770 4.000 330.170 ;
    END
  END wd_in[24]
  PIN wd_in[25]
    DIRECTION INPUT ;
    USE SIGNAL ;
    PORT
      LAYER met3 ;
      RECT 1.000 331.160 3.000 331.860 ;
    END
    PORT
      LAYER met3 ;
      RECT 1.000 330.810 4.000 332.210 ;
    END
  END wd_in[25]
  PIN wd_in[26]
    DIRECTION INPUT ;
    USE SIGNAL ;
    PORT
      LAYER met3 ;
      RECT 1.000 333.200 3.000 333.900 ;
    END
    PORT
      LAYER met3 ;
      RECT 1.000 332.850 4.000 334.250 ;
    END
  END wd_in[26]
  PIN wd_in[27]
    DIRECTION INPUT ;
    USE SIGNAL ;
    PORT
      LAYER met3 ;
      RECT 1.000 335.240 3.000 335.940 ;
    END
    PORT
      LAYER met3 ;
      RECT 1.000 334.890 4.000 336.290 ;
    END
  END wd_in[27]
  PIN wd_in[28]
    DIRECTION INPUT ;
    USE SIGNAL ;
    PORT
      LAYER met3 ;
      RECT 1.000 337.280 3.000 337.980 ;
    END
    PORT
      LAYER met3 ;
      RECT 1.000 336.930 4.000 338.330 ;
    END
  END wd_in[28]
  PIN wd_in[29]
    DIRECTION INPUT ;
    USE SIGNAL ;
    PORT
      LAYER met3 ;
      RECT 1.000 339.320 3.000 340.020 ;
    END
    PORT
      LAYER met3 ;
      RECT 1.000 338.970 4.000 340.370 ;
    END
  END wd_in[29]
  PIN wd_in[30]
    DIRECTION INPUT ;
    USE SIGNAL ;
    PORT
      LAYER met3 ;
      RECT 1.000 341.360 3.000 342.060 ;
    END
    PORT
      LAYER met3 ;
      RECT 1.000 341.010 4.000 342.410 ;
    END
  END wd_in[30]
  PIN wd_in[31]
    DIRECTION INPUT ;
    USE SIGNAL ;
    PORT
      LAYER met3 ;
      RECT 1.000 343.400 3.000 344.100 ;
    END
    PORT
      LAYER met3 ;
      RECT 1.000 343.050 4.000 344.450 ;
    END
  END wd_in[31]
  PIN wd_in[32]
    DIRECTION INPUT ;
    USE SIGNAL ;
    PORT
      LAYER met3 ;
      RECT 1.000 345.440 3.000 346.140 ;
    END
    PORT
      LAYER met3 ;
      RECT 1.000 345.090 4.000 346.490 ;
    END
  END wd_in[32]
  PIN wd_in[33]
    DIRECTION INPUT ;
    USE SIGNAL ;
    PORT
      LAYER met3 ;
      RECT 1.000 347.480 3.000 348.180 ;
    END
    PORT
      LAYER met3 ;
      RECT 1.000 347.130 4.000 348.530 ;
    END
  END wd_in[33]
  PIN wd_in[34]
    DIRECTION INPUT ;
    USE SIGNAL ;
    PORT
      LAYER met3 ;
      RECT 1.000 349.520 3.000 350.220 ;
    END
    PORT
      LAYER met3 ;
      RECT 1.000 349.170 4.000 350.570 ;
    END
  END wd_in[34]
  PIN wd_in[35]
    DIRECTION INPUT ;
    USE SIGNAL ;
    PORT
      LAYER met3 ;
      RECT 1.000 351.560 3.000 352.260 ;
    END
    PORT
      LAYER met3 ;
      RECT 1.000 351.210 4.000 352.610 ;
    END
  END wd_in[35]
  PIN wd_in[36]
    DIRECTION INPUT ;
    USE SIGNAL ;
    PORT
      LAYER met3 ;
      RECT 1.000 353.600 3.000 354.300 ;
    END
    PORT
      LAYER met3 ;
      RECT 1.000 353.250 4.000 354.650 ;
    END
  END wd_in[36]
  PIN wd_in[37]
    DIRECTION INPUT ;
    USE SIGNAL ;
    PORT
      LAYER met3 ;
      RECT 1.000 355.640 3.000 356.340 ;
    END
    PORT
      LAYER met3 ;
      RECT 1.000 355.290 4.000 356.690 ;
    END
  END wd_in[37]
  PIN wd_in[38]
    DIRECTION INPUT ;
    USE SIGNAL ;
    PORT
      LAYER met3 ;
      RECT 1.000 357.680 3.000 358.380 ;
    END
    PORT
      LAYER met3 ;
      RECT 1.000 357.330 4.000 358.730 ;
    END
  END wd_in[38]
  PIN wd_in[39]
    DIRECTION INPUT ;
    USE SIGNAL ;
    PORT
      LAYER met3 ;
      RECT 1.000 359.720 3.000 360.420 ;
    END
    PORT
      LAYER met3 ;
      RECT 1.000 359.370 4.000 360.770 ;
    END
  END wd_in[39]
  PIN wd_in[40]
    DIRECTION INPUT ;
    USE SIGNAL ;
    PORT
      LAYER met3 ;
      RECT 1.000 361.760 3.000 362.460 ;
    END
    PORT
      LAYER met3 ;
      RECT 1.000 361.410 4.000 362.810 ;
    END
  END wd_in[40]
  PIN wd_in[41]
    DIRECTION INPUT ;
    USE SIGNAL ;
    PORT
      LAYER met3 ;
      RECT 1.000 363.800 3.000 364.500 ;
    END
    PORT
      LAYER met3 ;
      RECT 1.000 363.450 4.000 364.850 ;
    END
  END wd_in[41]
  PIN wd_in[42]
    DIRECTION INPUT ;
    USE SIGNAL ;
    PORT
      LAYER met3 ;
      RECT 1.000 365.840 3.000 366.540 ;
    END
    PORT
      LAYER met3 ;
      RECT 1.000 365.490 4.000 366.890 ;
    END
  END wd_in[42]
  PIN wd_in[43]
    DIRECTION INPUT ;
    USE SIGNAL ;
    PORT
      LAYER met3 ;
      RECT 1.000 367.880 3.000 368.580 ;
    END
    PORT
      LAYER met3 ;
      RECT 1.000 367.530 4.000 368.930 ;
    END
  END wd_in[43]
  PIN wd_in[44]
    DIRECTION INPUT ;
    USE SIGNAL ;
    PORT
      LAYER met3 ;
      RECT 1.000 369.920 3.000 370.620 ;
    END
    PORT
      LAYER met3 ;
      RECT 1.000 369.570 4.000 370.970 ;
    END
  END wd_in[44]
  PIN wd_in[45]
    DIRECTION INPUT ;
    USE SIGNAL ;
    PORT
      LAYER met3 ;
      RECT 1.000 371.960 3.000 372.660 ;
    END
    PORT
      LAYER met3 ;
      RECT 1.000 371.610 4.000 373.010 ;
    END
  END wd_in[45]
  PIN wd_in[46]
    DIRECTION INPUT ;
    USE SIGNAL ;
    PORT
      LAYER met3 ;
      RECT 1.000 374.000 3.000 374.700 ;
    END
    PORT
      LAYER met3 ;
      RECT 1.000 373.650 4.000 375.050 ;
    END
  END wd_in[46]
  PIN wd_in[47]
    DIRECTION INPUT ;
    USE SIGNAL ;
    PORT
      LAYER met3 ;
      RECT 1.000 376.040 3.000 376.740 ;
    END
    PORT
      LAYER met3 ;
      RECT 1.000 375.690 4.000 377.090 ;
    END
  END wd_in[47]
  PIN wd_in[48]
    DIRECTION INPUT ;
    USE SIGNAL ;
    PORT
      LAYER met3 ;
      RECT 1.000 378.080 3.000 378.780 ;
    END
    PORT
      LAYER met3 ;
      RECT 1.000 377.730 4.000 379.130 ;
    END
  END wd_in[48]
  PIN wd_in[49]
    DIRECTION INPUT ;
    USE SIGNAL ;
    PORT
      LAYER met3 ;
      RECT 1.000 380.120 3.000 380.820 ;
    END
    PORT
      LAYER met3 ;
      RECT 1.000 379.770 4.000 381.170 ;
    END
  END wd_in[49]
  PIN wd_in[50]
    DIRECTION INPUT ;
    USE SIGNAL ;
    PORT
      LAYER met3 ;
      RECT 1.000 382.160 3.000 382.860 ;
    END
    PORT
      LAYER met3 ;
      RECT 1.000 381.810 4.000 383.210 ;
    END
  END wd_in[50]
  PIN wd_in[51]
    DIRECTION INPUT ;
    USE SIGNAL ;
    PORT
      LAYER met3 ;
      RECT 1.000 384.200 3.000 384.900 ;
    END
    PORT
      LAYER met3 ;
      RECT 1.000 383.850 4.000 385.250 ;
    END
  END wd_in[51]
  PIN wd_in[52]
    DIRECTION INPUT ;
    USE SIGNAL ;
    PORT
      LAYER met3 ;
      RECT 1.000 386.240 3.000 386.940 ;
    END
    PORT
      LAYER met3 ;
      RECT 1.000 385.890 4.000 387.290 ;
    END
  END wd_in[52]
  PIN wd_in[53]
    DIRECTION INPUT ;
    USE SIGNAL ;
    PORT
      LAYER met3 ;
      RECT 1.000 388.280 3.000 388.980 ;
    END
    PORT
      LAYER met3 ;
      RECT 1.000 387.930 4.000 389.330 ;
    END
  END wd_in[53]
  PIN wd_in[54]
    DIRECTION INPUT ;
    USE SIGNAL ;
    PORT
      LAYER met3 ;
      RECT 1.000 390.320 3.000 391.020 ;
    END
    PORT
      LAYER met3 ;
      RECT 1.000 389.970 4.000 391.370 ;
    END
  END wd_in[54]
  PIN wd_in[55]
    DIRECTION INPUT ;
    USE SIGNAL ;
    PORT
      LAYER met3 ;
      RECT 1.000 392.360 3.000 393.060 ;
    END
    PORT
      LAYER met3 ;
      RECT 1.000 392.010 4.000 393.410 ;
    END
  END wd_in[55]
  PIN wd_in[56]
    DIRECTION INPUT ;
    USE SIGNAL ;
    PORT
      LAYER met3 ;
      RECT 1.000 394.400 3.000 395.100 ;
    END
    PORT
      LAYER met3 ;
      RECT 1.000 394.050 4.000 395.450 ;
    END
  END wd_in[56]
  PIN wd_in[57]
    DIRECTION INPUT ;
    USE SIGNAL ;
    PORT
      LAYER met3 ;
      RECT 1.000 396.440 3.000 397.140 ;
    END
    PORT
      LAYER met3 ;
      RECT 1.000 396.090 4.000 397.490 ;
    END
  END wd_in[57]
  PIN wd_in[58]
    DIRECTION INPUT ;
    USE SIGNAL ;
    PORT
      LAYER met3 ;
      RECT 1.000 398.480 3.000 399.180 ;
    END
    PORT
      LAYER met3 ;
      RECT 1.000 398.130 4.000 399.530 ;
    END
  END wd_in[58]
  PIN wd_in[59]
    DIRECTION INPUT ;
    USE SIGNAL ;
    PORT
      LAYER met3 ;
      RECT 1.000 400.520 3.000 401.220 ;
    END
    PORT
      LAYER met3 ;
      RECT 1.000 400.170 4.000 401.570 ;
    END
  END wd_in[59]
  PIN wd_in[60]
    DIRECTION INPUT ;
    USE SIGNAL ;
    PORT
      LAYER met3 ;
      RECT 1.000 402.560 3.000 403.260 ;
    END
    PORT
      LAYER met3 ;
      RECT 1.000 402.210 4.000 403.610 ;
    END
  END wd_in[60]
  PIN wd_in[61]
    DIRECTION INPUT ;
    USE SIGNAL ;
    PORT
      LAYER met3 ;
      RECT 1.000 404.600 3.000 405.300 ;
    END
    PORT
      LAYER met3 ;
      RECT 1.000 404.250 4.000 405.650 ;
    END
  END wd_in[61]
  PIN wd_in[62]
    DIRECTION INPUT ;
    USE SIGNAL ;
    PORT
      LAYER met3 ;
      RECT 1.000 406.640 3.000 407.340 ;
    END
    PORT
      LAYER met3 ;
      RECT 1.000 406.290 4.000 407.690 ;
    END
  END wd_in[62]
  PIN wd_in[63]
    DIRECTION INPUT ;
    USE SIGNAL ;
    PORT
      LAYER met3 ;
      RECT 1.000 408.680 3.000 409.380 ;
    END
    PORT
      LAYER met3 ;
      RECT 1.000 408.330 4.000 409.730 ;
    END
  END wd_in[63]
  PIN wd_in[64]
    DIRECTION INPUT ;
    USE SIGNAL ;
    PORT
      LAYER met3 ;
      RECT 1.000 410.720 3.000 411.420 ;
    END
    PORT
      LAYER met3 ;
      RECT 1.000 410.370 4.000 411.770 ;
    END
  END wd_in[64]
  PIN wd_in[65]
    DIRECTION INPUT ;
    USE SIGNAL ;
    PORT
      LAYER met3 ;
      RECT 1.000 412.760 3.000 413.460 ;
    END
    PORT
      LAYER met3 ;
      RECT 1.000 412.410 4.000 413.810 ;
    END
  END wd_in[65]
  PIN wd_in[66]
    DIRECTION INPUT ;
    USE SIGNAL ;
    PORT
      LAYER met3 ;
      RECT 1.000 414.800 3.000 415.500 ;
    END
    PORT
      LAYER met3 ;
      RECT 1.000 414.450 4.000 415.850 ;
    END
  END wd_in[66]
  PIN wd_in[67]
    DIRECTION INPUT ;
    USE SIGNAL ;
    PORT
      LAYER met3 ;
      RECT 1.000 416.840 3.000 417.540 ;
    END
    PORT
      LAYER met3 ;
      RECT 1.000 416.490 4.000 417.890 ;
    END
  END wd_in[67]
  PIN wd_in[68]
    DIRECTION INPUT ;
    USE SIGNAL ;
    PORT
      LAYER met3 ;
      RECT 1.000 418.880 3.000 419.580 ;
    END
    PORT
      LAYER met3 ;
      RECT 1.000 418.530 4.000 419.930 ;
    END
  END wd_in[68]
  PIN wd_in[69]
    DIRECTION INPUT ;
    USE SIGNAL ;
    PORT
      LAYER met3 ;
      RECT 1.000 420.920 3.000 421.620 ;
    END
    PORT
      LAYER met3 ;
      RECT 1.000 420.570 4.000 421.970 ;
    END
  END wd_in[69]
  PIN wd_in[70]
    DIRECTION INPUT ;
    USE SIGNAL ;
    PORT
      LAYER met3 ;
      RECT 1.000 422.960 3.000 423.660 ;
    END
    PORT
      LAYER met3 ;
      RECT 1.000 422.610 4.000 424.010 ;
    END
  END wd_in[70]
  PIN wd_in[71]
    DIRECTION INPUT ;
    USE SIGNAL ;
    PORT
      LAYER met3 ;
      RECT 1.000 425.000 3.000 425.700 ;
    END
    PORT
      LAYER met3 ;
      RECT 1.000 424.650 4.000 426.050 ;
    END
  END wd_in[71]
  PIN wd_in[72]
    DIRECTION INPUT ;
    USE SIGNAL ;
    PORT
      LAYER met3 ;
      RECT 1.000 427.040 3.000 427.740 ;
    END
    PORT
      LAYER met3 ;
      RECT 1.000 426.690 4.000 428.090 ;
    END
  END wd_in[72]
  PIN wd_in[73]
    DIRECTION INPUT ;
    USE SIGNAL ;
    PORT
      LAYER met3 ;
      RECT 1.000 429.080 3.000 429.780 ;
    END
    PORT
      LAYER met3 ;
      RECT 1.000 428.730 4.000 430.130 ;
    END
  END wd_in[73]
  PIN wd_in[74]
    DIRECTION INPUT ;
    USE SIGNAL ;
    PORT
      LAYER met3 ;
      RECT 1.000 431.120 3.000 431.820 ;
    END
    PORT
      LAYER met3 ;
      RECT 1.000 430.770 4.000 432.170 ;
    END
  END wd_in[74]
  PIN wd_in[75]
    DIRECTION INPUT ;
    USE SIGNAL ;
    PORT
      LAYER met3 ;
      RECT 1.000 433.160 3.000 433.860 ;
    END
    PORT
      LAYER met3 ;
      RECT 1.000 432.810 4.000 434.210 ;
    END
  END wd_in[75]
  PIN wd_in[76]
    DIRECTION INPUT ;
    USE SIGNAL ;
    PORT
      LAYER met3 ;
      RECT 1.000 435.200 3.000 435.900 ;
    END
    PORT
      LAYER met3 ;
      RECT 1.000 434.850 4.000 436.250 ;
    END
  END wd_in[76]
  PIN wd_in[77]
    DIRECTION INPUT ;
    USE SIGNAL ;
    PORT
      LAYER met3 ;
      RECT 1.000 437.240 3.000 437.940 ;
    END
    PORT
      LAYER met3 ;
      RECT 1.000 436.890 4.000 438.290 ;
    END
  END wd_in[77]
  PIN wd_in[78]
    DIRECTION INPUT ;
    USE SIGNAL ;
    PORT
      LAYER met3 ;
      RECT 1.000 439.280 3.000 439.980 ;
    END
    PORT
      LAYER met3 ;
      RECT 1.000 438.930 4.000 440.330 ;
    END
  END wd_in[78]
  PIN wd_in[79]
    DIRECTION INPUT ;
    USE SIGNAL ;
    PORT
      LAYER met3 ;
      RECT 1.000 441.320 3.000 442.020 ;
    END
    PORT
      LAYER met3 ;
      RECT 1.000 440.970 4.000 442.370 ;
    END
  END wd_in[79]
  PIN wd_in[80]
    DIRECTION INPUT ;
    USE SIGNAL ;
    PORT
      LAYER met3 ;
      RECT 1.000 443.360 3.000 444.060 ;
    END
    PORT
      LAYER met3 ;
      RECT 1.000 443.010 4.000 444.410 ;
    END
  END wd_in[80]
  PIN wd_in[81]
    DIRECTION INPUT ;
    USE SIGNAL ;
    PORT
      LAYER met3 ;
      RECT 1.000 445.400 3.000 446.100 ;
    END
    PORT
      LAYER met3 ;
      RECT 1.000 445.050 4.000 446.450 ;
    END
  END wd_in[81]
  PIN wd_in[82]
    DIRECTION INPUT ;
    USE SIGNAL ;
    PORT
      LAYER met3 ;
      RECT 1.000 447.440 3.000 448.140 ;
    END
    PORT
      LAYER met3 ;
      RECT 1.000 447.090 4.000 448.490 ;
    END
  END wd_in[82]
  PIN wd_in[83]
    DIRECTION INPUT ;
    USE SIGNAL ;
    PORT
      LAYER met3 ;
      RECT 1.000 449.480 3.000 450.180 ;
    END
    PORT
      LAYER met3 ;
      RECT 1.000 449.130 4.000 450.530 ;
    END
  END wd_in[83]
  PIN wd_in[84]
    DIRECTION INPUT ;
    USE SIGNAL ;
    PORT
      LAYER met3 ;
      RECT 1.000 451.520 3.000 452.220 ;
    END
    PORT
      LAYER met3 ;
      RECT 1.000 451.170 4.000 452.570 ;
    END
  END wd_in[84]
  PIN wd_in[85]
    DIRECTION INPUT ;
    USE SIGNAL ;
    PORT
      LAYER met3 ;
      RECT 1.000 453.560 3.000 454.260 ;
    END
    PORT
      LAYER met3 ;
      RECT 1.000 453.210 4.000 454.610 ;
    END
  END wd_in[85]
  PIN wd_in[86]
    DIRECTION INPUT ;
    USE SIGNAL ;
    PORT
      LAYER met3 ;
      RECT 1.000 455.600 3.000 456.300 ;
    END
    PORT
      LAYER met3 ;
      RECT 1.000 455.250 4.000 456.650 ;
    END
  END wd_in[86]
  PIN wd_in[87]
    DIRECTION INPUT ;
    USE SIGNAL ;
    PORT
      LAYER met3 ;
      RECT 1.000 457.640 3.000 458.340 ;
    END
    PORT
      LAYER met3 ;
      RECT 1.000 457.290 4.000 458.690 ;
    END
  END wd_in[87]
  PIN wd_in[88]
    DIRECTION INPUT ;
    USE SIGNAL ;
    PORT
      LAYER met3 ;
      RECT 1.000 459.680 3.000 460.380 ;
    END
    PORT
      LAYER met3 ;
      RECT 1.000 459.330 4.000 460.730 ;
    END
  END wd_in[88]
  PIN wd_in[89]
    DIRECTION INPUT ;
    USE SIGNAL ;
    PORT
      LAYER met3 ;
      RECT 1.000 461.720 3.000 462.420 ;
    END
    PORT
      LAYER met3 ;
      RECT 1.000 461.370 4.000 462.770 ;
    END
  END wd_in[89]
  PIN wd_in[90]
    DIRECTION INPUT ;
    USE SIGNAL ;
    PORT
      LAYER met3 ;
      RECT 1.000 463.760 3.000 464.460 ;
    END
    PORT
      LAYER met3 ;
      RECT 1.000 463.410 4.000 464.810 ;
    END
  END wd_in[90]
  PIN wd_in[91]
    DIRECTION INPUT ;
    USE SIGNAL ;
    PORT
      LAYER met3 ;
      RECT 1.000 465.800 3.000 466.500 ;
    END
    PORT
      LAYER met3 ;
      RECT 1.000 465.450 4.000 466.850 ;
    END
  END wd_in[91]
  PIN wd_in[92]
    DIRECTION INPUT ;
    USE SIGNAL ;
    PORT
      LAYER met3 ;
      RECT 1.000 467.840 3.000 468.540 ;
    END
    PORT
      LAYER met3 ;
      RECT 1.000 467.490 4.000 468.890 ;
    END
  END wd_in[92]
  PIN wd_in[93]
    DIRECTION INPUT ;
    USE SIGNAL ;
    PORT
      LAYER met3 ;
      RECT 1.000 469.880 3.000 470.580 ;
    END
    PORT
      LAYER met3 ;
      RECT 1.000 469.530 4.000 470.930 ;
    END
  END wd_in[93]
  PIN wd_in[94]
    DIRECTION INPUT ;
    USE SIGNAL ;
    PORT
      LAYER met3 ;
      RECT 1.000 471.920 3.000 472.620 ;
    END
    PORT
      LAYER met3 ;
      RECT 1.000 471.570 4.000 472.970 ;
    END
  END wd_in[94]
  PIN wd_in[95]
    DIRECTION INPUT ;
    USE SIGNAL ;
    PORT
      LAYER met3 ;
      RECT 1.000 473.960 3.000 474.660 ;
    END
    PORT
      LAYER met3 ;
      RECT 1.000 473.610 4.000 475.010 ;
    END
  END wd_in[95]
  PIN wd_in[96]
    DIRECTION INPUT ;
    USE SIGNAL ;
    PORT
      LAYER met3 ;
      RECT 1.000 476.000 3.000 476.700 ;
    END
    PORT
      LAYER met3 ;
      RECT 1.000 475.650 4.000 477.050 ;
    END
  END wd_in[96]
  PIN wd_in[97]
    DIRECTION INPUT ;
    USE SIGNAL ;
    PORT
      LAYER met3 ;
      RECT 1.000 478.040 3.000 478.740 ;
    END
    PORT
      LAYER met3 ;
      RECT 1.000 477.690 4.000 479.090 ;
    END
  END wd_in[97]
  PIN wd_in[98]
    DIRECTION INPUT ;
    USE SIGNAL ;
    PORT
      LAYER met3 ;
      RECT 1.000 480.080 3.000 480.780 ;
    END
    PORT
      LAYER met3 ;
      RECT 1.000 479.730 4.000 481.130 ;
    END
  END wd_in[98]
  PIN wd_in[99]
    DIRECTION INPUT ;
    USE SIGNAL ;
    PORT
      LAYER met3 ;
      RECT 1.000 482.120 3.000 482.820 ;
    END
    PORT
      LAYER met3 ;
      RECT 1.000 481.770 4.000 483.170 ;
    END
  END wd_in[99]
  PIN wd_in[100]
    DIRECTION INPUT ;
    USE SIGNAL ;
    PORT
      LAYER met3 ;
      RECT 1.000 484.160 3.000 484.860 ;
    END
    PORT
      LAYER met3 ;
      RECT 1.000 483.810 4.000 485.210 ;
    END
  END wd_in[100]
  PIN wd_in[101]
    DIRECTION INPUT ;
    USE SIGNAL ;
    PORT
      LAYER met3 ;
      RECT 1.000 486.200 3.000 486.900 ;
    END
    PORT
      LAYER met3 ;
      RECT 1.000 485.850 4.000 487.250 ;
    END
  END wd_in[101]
  PIN wd_in[102]
    DIRECTION INPUT ;
    USE SIGNAL ;
    PORT
      LAYER met3 ;
      RECT 1.000 488.240 3.000 488.940 ;
    END
    PORT
      LAYER met3 ;
      RECT 1.000 487.890 4.000 489.290 ;
    END
  END wd_in[102]
  PIN wd_in[103]
    DIRECTION INPUT ;
    USE SIGNAL ;
    PORT
      LAYER met3 ;
      RECT 1.000 490.280 3.000 490.980 ;
    END
    PORT
      LAYER met3 ;
      RECT 1.000 489.930 4.000 491.330 ;
    END
  END wd_in[103]
  PIN wd_in[104]
    DIRECTION INPUT ;
    USE SIGNAL ;
    PORT
      LAYER met3 ;
      RECT 1.000 492.320 3.000 493.020 ;
    END
    PORT
      LAYER met3 ;
      RECT 1.000 491.970 4.000 493.370 ;
    END
  END wd_in[104]
  PIN wd_in[105]
    DIRECTION INPUT ;
    USE SIGNAL ;
    PORT
      LAYER met3 ;
      RECT 1.000 494.360 3.000 495.060 ;
    END
    PORT
      LAYER met3 ;
      RECT 1.000 494.010 4.000 495.410 ;
    END
  END wd_in[105]
  PIN wd_in[106]
    DIRECTION INPUT ;
    USE SIGNAL ;
    PORT
      LAYER met3 ;
      RECT 1.000 496.400 3.000 497.100 ;
    END
    PORT
      LAYER met3 ;
      RECT 1.000 496.050 4.000 497.450 ;
    END
  END wd_in[106]
  PIN wd_in[107]
    DIRECTION INPUT ;
    USE SIGNAL ;
    PORT
      LAYER met3 ;
      RECT 1.000 498.440 3.000 499.140 ;
    END
    PORT
      LAYER met3 ;
      RECT 1.000 498.090 4.000 499.490 ;
    END
  END wd_in[107]
  PIN wd_in[108]
    DIRECTION INPUT ;
    USE SIGNAL ;
    PORT
      LAYER met3 ;
      RECT 1.000 500.480 3.000 501.180 ;
    END
    PORT
      LAYER met3 ;
      RECT 1.000 500.130 4.000 501.530 ;
    END
  END wd_in[108]
  PIN wd_in[109]
    DIRECTION INPUT ;
    USE SIGNAL ;
    PORT
      LAYER met3 ;
      RECT 1.000 502.520 3.000 503.220 ;
    END
    PORT
      LAYER met3 ;
      RECT 1.000 502.170 4.000 503.570 ;
    END
  END wd_in[109]
  PIN wd_in[110]
    DIRECTION INPUT ;
    USE SIGNAL ;
    PORT
      LAYER met3 ;
      RECT 1.000 504.560 3.000 505.260 ;
    END
    PORT
      LAYER met3 ;
      RECT 1.000 504.210 4.000 505.610 ;
    END
  END wd_in[110]
  PIN wd_in[111]
    DIRECTION INPUT ;
    USE SIGNAL ;
    PORT
      LAYER met3 ;
      RECT 1.000 506.600 3.000 507.300 ;
    END
    PORT
      LAYER met3 ;
      RECT 1.000 506.250 4.000 507.650 ;
    END
  END wd_in[111]
  PIN wd_in[112]
    DIRECTION INPUT ;
    USE SIGNAL ;
    PORT
      LAYER met3 ;
      RECT 1.000 508.640 3.000 509.340 ;
    END
    PORT
      LAYER met3 ;
      RECT 1.000 508.290 4.000 509.690 ;
    END
  END wd_in[112]
  PIN wd_in[113]
    DIRECTION INPUT ;
    USE SIGNAL ;
    PORT
      LAYER met3 ;
      RECT 1.000 510.680 3.000 511.380 ;
    END
    PORT
      LAYER met3 ;
      RECT 1.000 510.330 4.000 511.730 ;
    END
  END wd_in[113]
  PIN wd_in[114]
    DIRECTION INPUT ;
    USE SIGNAL ;
    PORT
      LAYER met3 ;
      RECT 1.000 512.720 3.000 513.420 ;
    END
    PORT
      LAYER met3 ;
      RECT 1.000 512.370 4.000 513.770 ;
    END
  END wd_in[114]
  PIN wd_in[115]
    DIRECTION INPUT ;
    USE SIGNAL ;
    PORT
      LAYER met3 ;
      RECT 1.000 514.760 3.000 515.460 ;
    END
    PORT
      LAYER met3 ;
      RECT 1.000 514.410 4.000 515.810 ;
    END
  END wd_in[115]
  PIN wd_in[116]
    DIRECTION INPUT ;
    USE SIGNAL ;
    PORT
      LAYER met3 ;
      RECT 1.000 516.800 3.000 517.500 ;
    END
    PORT
      LAYER met3 ;
      RECT 1.000 516.450 4.000 517.850 ;
    END
  END wd_in[116]
  PIN wd_in[117]
    DIRECTION INPUT ;
    USE SIGNAL ;
    PORT
      LAYER met3 ;
      RECT 1.000 518.840 3.000 519.540 ;
    END
    PORT
      LAYER met3 ;
      RECT 1.000 518.490 4.000 519.890 ;
    END
  END wd_in[117]
  PIN wd_in[118]
    DIRECTION INPUT ;
    USE SIGNAL ;
    PORT
      LAYER met3 ;
      RECT 1.000 520.880 3.000 521.580 ;
    END
    PORT
      LAYER met3 ;
      RECT 1.000 520.530 4.000 521.930 ;
    END
  END wd_in[118]
  PIN wd_in[119]
    DIRECTION INPUT ;
    USE SIGNAL ;
    PORT
      LAYER met3 ;
      RECT 1.000 522.920 3.000 523.620 ;
    END
    PORT
      LAYER met3 ;
      RECT 1.000 522.570 4.000 523.970 ;
    END
  END wd_in[119]
  PIN wd_in[120]
    DIRECTION INPUT ;
    USE SIGNAL ;
    PORT
      LAYER met3 ;
      RECT 1.000 524.960 3.000 525.660 ;
    END
    PORT
      LAYER met3 ;
      RECT 1.000 524.610 4.000 526.010 ;
    END
  END wd_in[120]
  PIN wd_in[121]
    DIRECTION INPUT ;
    USE SIGNAL ;
    PORT
      LAYER met3 ;
      RECT 1.000 527.000 3.000 527.700 ;
    END
    PORT
      LAYER met3 ;
      RECT 1.000 526.650 4.000 528.050 ;
    END
  END wd_in[121]
  PIN wd_in[122]
    DIRECTION INPUT ;
    USE SIGNAL ;
    PORT
      LAYER met3 ;
      RECT 1.000 529.040 3.000 529.740 ;
    END
    PORT
      LAYER met3 ;
      RECT 1.000 528.690 4.000 530.090 ;
    END
  END wd_in[122]
  PIN wd_in[123]
    DIRECTION INPUT ;
    USE SIGNAL ;
    PORT
      LAYER met3 ;
      RECT 1.000 531.080 3.000 531.780 ;
    END
    PORT
      LAYER met3 ;
      RECT 1.000 530.730 4.000 532.130 ;
    END
  END wd_in[123]
  PIN wd_in[124]
    DIRECTION INPUT ;
    USE SIGNAL ;
    PORT
      LAYER met3 ;
      RECT 1.000 533.120 3.000 533.820 ;
    END
    PORT
      LAYER met3 ;
      RECT 1.000 532.770 4.000 534.170 ;
    END
  END wd_in[124]
  PIN wd_in[125]
    DIRECTION INPUT ;
    USE SIGNAL ;
    PORT
      LAYER met3 ;
      RECT 1.000 535.160 3.000 535.860 ;
    END
    PORT
      LAYER met3 ;
      RECT 1.000 534.810 4.000 536.210 ;
    END
  END wd_in[125]
  PIN wd_in[126]
    DIRECTION INPUT ;
    USE SIGNAL ;
    PORT
      LAYER met3 ;
      RECT 1.000 537.200 3.000 537.900 ;
    END
    PORT
      LAYER met3 ;
      RECT 1.000 536.850 4.000 538.250 ;
    END
  END wd_in[126]
  PIN wd_in[127]
    DIRECTION INPUT ;
    USE SIGNAL ;
    PORT
      LAYER met3 ;
      RECT 1.000 539.240 3.000 539.940 ;
    END
    PORT
      LAYER met3 ;
      RECT 1.000 538.890 4.000 540.290 ;
    END
  END wd_in[127]
  PIN addr_in[0]
    DIRECTION INPUT ;
    USE SIGNAL ;
    PORT
      LAYER met3 ;
      RECT 1.000 559.640 3.000 560.340 ;
    END
    PORT
      LAYER met3 ;
      RECT 1.000 559.290 4.000 560.690 ;
    END
  END addr_in[0]
  PIN addr_in[1]
    DIRECTION INPUT ;
    USE SIGNAL ;
    PORT
      LAYER met3 ;
      RECT 1.000 561.680 3.000 562.380 ;
    END
    PORT
      LAYER met3 ;
      RECT 1.000 561.330 4.000 562.730 ;
    END
  END addr_in[1]
  PIN addr_in[2]
    DIRECTION INPUT ;
    USE SIGNAL ;
    PORT
      LAYER met3 ;
      RECT 1.000 563.720 3.000 564.420 ;
    END
    PORT
      LAYER met3 ;
      RECT 1.000 563.370 4.000 564.770 ;
    END
  END addr_in[2]
  PIN addr_in[3]
    DIRECTION INPUT ;
    USE SIGNAL ;
    PORT
      LAYER met3 ;
      RECT 1.000 565.760 3.000 566.460 ;
    END
    PORT
      LAYER met3 ;
      RECT 1.000 565.410 4.000 566.810 ;
    END
  END addr_in[3]
  PIN addr_in[4]
    DIRECTION INPUT ;
    USE SIGNAL ;
    PORT
      LAYER met3 ;
      RECT 1.000 567.800 3.000 568.500 ;
    END
    PORT
      LAYER met3 ;
      RECT 1.000 567.450 4.000 568.850 ;
    END
  END addr_in[4]
  PIN addr_in[5]
    DIRECTION INPUT ;
    USE SIGNAL ;
    PORT
      LAYER met3 ;
      RECT 1.000 569.840 3.000 570.540 ;
    END
    PORT
      LAYER met3 ;
      RECT 1.000 569.490 4.000 570.890 ;
    END
  END addr_in[5]
  PIN we_in
    DIRECTION INPUT ;
    USE SIGNAL ;
    PORT
      LAYER met3 ;
      RECT 1.000 590.240 3.000 590.940 ;
    END
    PORT
      LAYER met3 ;
      RECT 1.000 589.890 4.000 591.290 ;
    END
  END we_in
  PIN ce_in
    DIRECTION INPUT ;
    USE SIGNAL ;
    PORT
      LAYER met3 ;
      RECT 1.000 592.280 3.000 592.980 ;
    END
    PORT
      LAYER met3 ;
      RECT 1.000 591.930 4.000 593.330 ;
    END
  END ce_in
  PIN clk
    DIRECTION INPUT ;
    USE SIGNAL ;
    PORT
      LAYER met3 ;
      RECT 1.000 594.320 3.000 595.020 ;
    END
    PORT
      LAYER met3 ;
      RECT 1.000 593.970 4.000 595.370 ;
    END
  END clk
  PIN VSS
    DIRECTION INOUT ;
    USE GROUND ;
    PORT
      LAYER met3 ;
      RECT 0.680 -0.720 237.320 2.080 ;
      RECT 0.680 10.160 237.320 12.960 ;
      RECT 0.680 21.040 237.320 23.840 ;
      RECT 0.680 31.920 237.320 34.720 ;
      RECT 0.680 42.800 237.320 45.600 ;
      RECT 0.680 53.680 237.320 56.480 ;
      RECT 0.680 64.560 237.320 67.360 ;
      RECT 0.680 75.440 237.320 78.240 ;
      RECT 0.680 86.320 237.320 89.120 ;
      RECT 0.680 97.200 237.320 100.000 ;
      RECT 0.680 108.080 237.320 110.880 ;
      RECT 0.680 118.960 237.320 121.760 ;
      RECT 0.680 129.840 237.320 132.640 ;
      RECT 0.680 140.720 237.320 143.520 ;
      RECT 0.680 151.600 237.320 154.400 ;
      RECT 0.680 162.480 237.320 165.280 ;
      RECT 0.680 173.360 237.320 176.160 ;
      RECT 0.680 184.240 237.320 187.040 ;
      RECT 0.680 195.120 237.320 197.920 ;
      RECT 0.680 206.000 237.320 208.800 ;
      RECT 0.680 216.880 237.320 219.680 ;
      RECT 0.680 227.760 237.320 230.560 ;
      RECT 0.680 238.640 237.320 241.440 ;
      RECT 0.680 249.520 237.320 252.320 ;
      RECT 0.680 260.400 237.320 263.200 ;
      RECT 0.680 271.280 237.320 274.080 ;
      RECT 0.680 282.160 237.320 284.960 ;
      RECT 0.680 293.040 237.320 295.840 ;
      RECT 0.680 303.920 237.320 306.720 ;
      RECT 0.680 314.800 237.320 317.600 ;
      RECT 0.680 325.680 237.320 328.480 ;
      RECT 0.680 336.560 237.320 339.360 ;
      RECT 0.680 347.440 237.320 350.240 ;
      RECT 0.680 358.320 237.320 361.120 ;
      RECT 0.680 369.200 237.320 372.000 ;
      RECT 0.680 380.080 237.320 382.880 ;
      RECT 0.680 390.960 237.320 393.760 ;
      RECT 0.680 401.840 237.320 404.640 ;
      RECT 0.680 412.720 237.320 415.520 ;
      RECT 0.680 423.600 237.320 426.400 ;
      RECT 0.680 434.480 237.320 437.280 ;
      RECT 0.680 445.360 237.320 448.160 ;
      RECT 0.680 456.240 237.320 459.040 ;
      RECT 0.680 467.120 237.320 469.920 ;
      RECT 0.680 478.000 237.320 480.800 ;
      RECT 0.680 488.880 237.320 491.680 ;
      RECT 0.680 499.760 237.320 502.560 ;
      RECT 0.680 510.640 237.320 513.440 ;
      RECT 0.680 521.520 237.320 524.320 ;
      RECT 0.680 532.400 237.320 535.200 ;
      RECT 0.680 543.280 237.320 546.080 ;
      RECT 0.680 554.160 237.320 556.960 ;
      RECT 0.680 565.040 237.320 567.840 ;
      RECT 0.680 575.920 237.320 578.720 ;
      RECT 0.680 586.800 237.320 589.600 ;
    END
  END VSS
  PIN VDD
    DIRECTION INOUT ;
    USE POWER ;
    PORT
      LAYER met3 ;
      RECT 0.680 4.720 237.320 7.520 ;
      RECT 0.680 15.600 237.320 18.400 ;
      RECT 0.680 26.480 237.320 29.280 ;
      RECT 0.680 37.360 237.320 40.160 ;
      RECT 0.680 48.240 237.320 51.040 ;
      RECT 0.680 59.120 237.320 61.920 ;
      RECT 0.680 70.000 237.320 72.800 ;
      RECT 0.680 80.880 237.320 83.680 ;
      RECT 0.680 91.760 237.320 94.560 ;
      RECT 0.680 102.640 237.320 105.440 ;
      RECT 0.680 113.520 237.320 116.320 ;
      RECT 0.680 124.400 237.320 127.200 ;
      RECT 0.680 135.280 237.320 138.080 ;
      RECT 0.680 146.160 237.320 148.960 ;
      RECT 0.680 157.040 237.320 159.840 ;
      RECT 0.680 167.920 237.320 170.720 ;
      RECT 0.680 178.800 237.320 181.600 ;
      RECT 0.680 189.680 237.320 192.480 ;
      RECT 0.680 200.560 237.320 203.360 ;
      RECT 0.680 211.440 237.320 214.240 ;
      RECT 0.680 222.320 237.320 225.120 ;
      RECT 0.680 233.200 237.320 236.000 ;
      RECT 0.680 244.080 237.320 246.880 ;
      RECT 0.680 254.960 237.320 257.760 ;
      RECT 0.680 265.840 237.320 268.640 ;
      RECT 0.680 276.720 237.320 279.520 ;
      RECT 0.680 287.600 237.320 290.400 ;
      RECT 0.680 298.480 237.320 301.280 ;
      RECT 0.680 309.360 237.320 312.160 ;
      RECT 0.680 320.240 237.320 323.040 ;
      RECT 0.680 331.120 237.320 333.920 ;
      RECT 0.680 342.000 237.320 344.800 ;
      RECT 0.680 352.880 237.320 355.680 ;
      RECT 0.680 363.760 237.320 366.560 ;
      RECT 0.680 374.640 237.320 377.440 ;
      RECT 0.680 385.520 237.320 388.320 ;
      RECT 0.680 396.400 237.320 399.200 ;
      RECT 0.680 407.280 237.320 410.080 ;
      RECT 0.680 418.160 237.320 420.960 ;
      RECT 0.680 429.040 237.320 431.840 ;
      RECT 0.680 439.920 237.320 442.720 ;
      RECT 0.680 450.800 237.320 453.600 ;
      RECT 0.680 461.680 237.320 464.480 ;
      RECT 0.680 472.560 237.320 475.360 ;
      RECT 0.680 483.440 237.320 486.240 ;
      RECT 0.680 494.320 237.320 497.120 ;
      RECT 0.680 505.200 237.320 508.000 ;
      RECT 0.680 516.080 237.320 518.880 ;
      RECT 0.680 526.960 237.320 529.760 ;
      RECT 0.680 537.840 237.320 540.640 ;
      RECT 0.680 548.720 237.320 551.520 ;
      RECT 0.680 559.600 237.320 562.400 ;
      RECT 0.680 570.480 237.320 573.280 ;
      RECT 0.680 581.360 237.320 584.160 ;
      RECT 0.680 592.240 237.320 595.040 ;
    END
  END VDD
  OBS
    LAYER met1 ;
    RECT 0 0 238.000 598.000 ;
    LAYER met2 ;
    RECT 0 0 238.000 598.000 ;
  END
END fakeram_128x64
END LIBRARY
